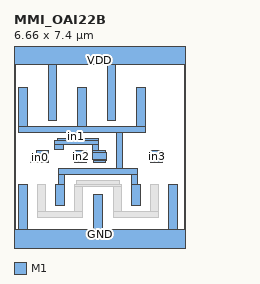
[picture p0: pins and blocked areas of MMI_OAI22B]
MACRO MMI_OAI22B
	CLASS CORE ;
	FOREIGN MMI_OAI22B 0 0 ;
	SIZE 6.66 BY 7.4 ;
	SYMMETRY X Y ;
	SITE CORE1 ;
	PIN out
		DIRECTION output ;
		USE SIGNAL ;
		PORT
			LAYER M1 ;
			RECT 0.18 4.485 0.52 6.025 ;
			LAYER M1 ;
			RECT 2.48 4.485 2.82 6.025 ;
			LAYER M1 ;
			RECT 4.78 4.485 5.12 6.025 ;
			LAYER M1 ;
			RECT 0.18 4.255 5.12 4.485 ;
			LAYER M1 ;
			RECT 3.99 2.875 4.22 4.255 ;
			LAYER M1 ;
			RECT 1.73 2.645 4.81 2.875 ;
			LAYER M1 ;
			RECT 1.73 2.245 1.96 2.645 ;
			LAYER M1 ;
			RECT 1.62 1.405 1.96 2.245 ;
			LAYER M1 ;
			RECT 4.58 2.245 4.81 2.645 ;
			LAYER M1 ;
			RECT 4.58 1.405 4.92 2.245 ;
		END
		AntennaDiffArea 3.7536 ;
	END out
	PIN in1
		DIRECTION input ;
		USE SIGNAL ;
		PORT
			LAYER M1 ;
			RECT 1.675 3.94 3.295 4.015 ;
			LAYER M1 ;
			RECT 1.57 3.785 3.295 3.94 ;
			LAYER M1 ;
			RECT 1.57 3.6 1.91 3.785 ;
			LAYER M1 ;
			RECT 3.065 3.555 3.295 3.785 ;
			LAYER M1 ;
			RECT 3.065 3.5 3.555 3.555 ;
			LAYER M1 ;
			RECT 3.065 3.215 3.59 3.5 ;
			LAYER M1 ;
			RECT 3.105 3.16 3.59 3.215 ;
			LAYER M1 ;
			RECT 3.105 3.105 3.555 3.16 ;
		END
		AntennaGateArea 0.9936 ;
	END in1
	PIN GND
		DIRECTION inout ;
		USE GROUND ;
		PORT
			LAYER M1 ;
			RECT 0.18 0.5 0.52 2.245 ;
			LAYER M1 ;
			RECT 3.1 0.5 3.44 1.845 ;
			LAYER M1 ;
			RECT 6.02 0.5 6.36 2.245 ;
			LAYER M1 ;
			RECT 0 -0.5 6.66 0.5 ;
		END
	END GND
	PIN in2
		DIRECTION input ;
		USE SIGNAL ;
		PORT
			LAYER M1 ;
			RECT 2.365 3.105 2.815 3.555 ;
		END
		AntennaGateArea 0.9936 ;
	END in2
	PIN VDD
		DIRECTION inout ;
		USE POWER ;
		PORT
			LAYER M1 ;
			RECT 0 6.9 6.66 7.9 ;
			LAYER M1 ;
			RECT 1.33 4.745 1.67 6.9 ;
			LAYER M1 ;
			RECT 3.63 4.745 3.97 6.9 ;
		END
	END VDD
	PIN in3
		DIRECTION input ;
		USE SIGNAL ;
		PORT
			LAYER M1 ;
			RECT 5.325 3.105 5.775 3.555 ;
		END
		AntennaGateArea 0.9936 ;
	END in3
	PIN in0
		DIRECTION input ;
		USE SIGNAL ;
		PORT
			LAYER M1 ;
			RECT 0.885 3.445 1.335 3.555 ;
			LAYER M1 ;
			RECT 0.66 3.105 1.335 3.445 ;
		END
		AntennaGateArea 0.9936 ;
	END in0
	OBS
		LAYER M1 ;
		RECT 2.45 2.245 4.09 2.405 ;
		LAYER M1 ;
		RECT 0.9 1.175 1.24 2.245 ;
		LAYER M1 ;
		RECT 2.34 2.175 4.2 2.245 ;
		LAYER M1 ;
		RECT 2.34 1.175 2.68 2.175 ;
		LAYER M1 ;
		RECT 0.9 0.945 2.68 1.175 ;
		LAYER M1 ;
		RECT 3.86 1.175 4.2 2.175 ;
		LAYER M1 ;
		RECT 5.3 1.175 5.64 2.245 ;
		LAYER M1 ;
		RECT 3.86 0.945 5.64 1.175 ;
	END
END MMI_OAI22B
